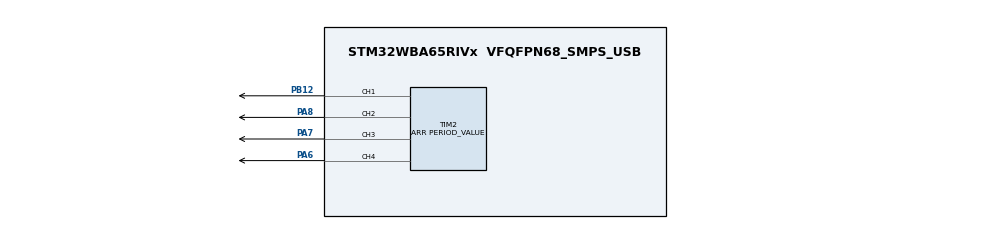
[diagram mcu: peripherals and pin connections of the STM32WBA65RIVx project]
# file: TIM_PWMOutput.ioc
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CORTEX_M33_NS.userName=CORTEX_M33
Mcu.Family=STM32WBA
Mcu.Name=STM32WBA65RIVx
Mcu.Package=VFQFPN68_SMPS_USB
NVIC.PriorityGroup=NVIC_PRIORITYGROUP_4
OSC_IN.Mode=HSE-External-Oscillator
OSC_IN.PinAttribute=CortexM33
OSC_IN.Signal=RCC_OSC_IN
OSC_OUT.Mode=HSE-External-Oscillator
OSC_OUT.PinAttribute=CortexM33
OSC_OUT.Signal=RCC_OSC_OUT
PA6.GPIO_PuPd=GPIO_PULLUP
PA6.GPIO_Speed=GPIO_SPEED_FREQ_HIGH
PA6.PinAttribute=CortexM33
PA6.Signal=S_TIM2_CH4
PA7.GPIO_PuPd=GPIO_PULLUP
PA7.GPIO_Speed=GPIO_SPEED_FREQ_HIGH
PA7.PinAttribute=CortexM33
PA7.Signal=S_TIM2_CH3
PA8.GPIO_PuPd=GPIO_PULLUP
PA8.GPIO_Speed=GPIO_SPEED_FREQ_HIGH
PA8.PinAttribute=CortexM33
PA8.Signal=S_TIM2_CH2
PB12.GPIO_PuPd=GPIO_PULLUP
PB12.GPIO_Speed=GPIO_SPEED_FREQ_HIGH
PB12.PinAttribute=CortexM33
PB12.Signal=S_TIM2_CH1
ProjectManager.HeapSize=0x200
ProjectManager.StackSize=0x400
ProjectManager.TargetToolchain=EWARM V9.20
RCC.ADCFreq_Value=100000000
RCC.AHB5CLKDivider=DIV4
RCC.AHBFreq_Value=100000000
RCC.APB1Freq_Value=100000000
RCC.APB1TimFreq_Value=100000000
RCC.APB2Freq_Value=100000000
RCC.APB2TimFreq_Value=100000000
RCC.CortexFreq_Value=12500000
RCC.HCLKFreq_Value=100000000
RCC.HSE_VALUE=32000000
RCC.HSI_VALUE=16000000
RCC.LSE_VALUE=32768
RCC.LSI1_VALUE=32000
RCC.LSI2_VALUE=32000
RCC.PLLFRACN=4096
RCC.PLLM=2
RCC.PLLN=12
RCC.PLLSourceVirtual=RCC_PLLSOURCE_HSE
RCC.SYSCLKFreq_VALUE=100000000
RCC.SYSCLKSourceVirtual=RCC_SYSCLKSOURCE_PLLCLK
RCC.VCOOutputFreq_Value=200000000
SH.S_TIM2_CH1.0=TIM2_CH1,PWM Generation1 CH1
SH.S_TIM2_CH2.0=TIM2_CH2,PWM Generation2 CH2
SH.S_TIM2_CH3.0=TIM2_CH3,PWM Generation3 CH3
SH.S_TIM2_CH4.0=TIM2_CH4,PWM Generation4 CH4
TIM2.AutoReloadPreload=TIM_AUTORELOAD_PRELOAD_DISABLE
TIM2.Channel-PWM\ Generation1\ CH1=TIM_CHANNEL_1
TIM2.Channel-PWM\ Generation2\ CH2=TIM_CHANNEL_2
TIM2.Channel-PWM\ Generation3\ CH3=TIM_CHANNEL_3
TIM2.Channel-PWM\ Generation4\ CH4=TIM_CHANNEL_4
TIM2.ClearInputSource=TIM_CLEARINPUTSOURCE_NONE
TIM2.ClockDivision=TIM_CLOCKDIVISION_DIV1
TIM2.CounterMode=TIM_COUNTERMODE_UP
TIM2.OC1Preload_PWM=ENABLE
TIM2.OC2Preload_PWM=ENABLE
TIM2.OC3Preload_PWM=ENABLE
TIM2.OC4Preload_PWM=ENABLE
TIM2.OCFastMode_PWM-PWM\ Generation1\ CH1=TIM_OCFAST_DISABLE
TIM2.OCFastMode_PWM-PWM\ Generation2\ CH2=TIM_OCFAST_DISABLE
TIM2.OCFastMode_PWM-PWM\ Generation3\ CH3=TIM_OCFAST_DISABLE
TIM2.OCFastMode_PWM-PWM\ Generation4\ CH4=TIM_OCFAST_DISABLE
TIM2.OCMode_PWM-PWM\ Generation1\ CH1=TIM_OCMODE_PWM1
TIM2.OCMode_PWM-PWM\ Generation2\ CH2=TIM_OCMODE_PWM1
TIM2.OCMode_PWM-PWM\ Generation3\ CH3=TIM_OCMODE_PWM1
TIM2.OCMode_PWM-PWM\ Generation4\ CH4=TIM_OCMODE_PWM1
TIM2.OCPolarity_1=TIM_OCPOLARITY_HIGH
TIM2.OCPolarity_2=TIM_OCPOLARITY_HIGH
TIM2.OCPolarity_3=TIM_OCPOLARITY_HIGH
TIM2.OCPolarity_4=TIM_OCPOLARITY_HIGH
TIM2.Period=PERIOD_VALUE
TIM2.Prescaler=PRESCALER_VALUE
TIM2.PulseNoDither_1=PULSE1_VALUE
TIM2.PulseNoDither_2=PULSE2_VALUE
TIM2.PulseNoDither_3=PULSE3_VALUE
TIM2.PulseNoDither_4=PULSE4_VALUE
TIM2.TIM_MasterOutputTrigger=TIM_TRGO_RESET
TIM2.TIM_MasterSlaveMode=TIM_MASTERSLAVEMODE_DISABLE
VP_CORTEX_M33_NS_VS_Hclk.Mode=Hclk_Mode
VP_ICACHE_VS_ICACHE.Mode=DirectMappedCache
VP_PWR_VS_SECSignals.Mode=Security/Privilege
board=custom

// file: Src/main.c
/* USER CODE BEGIN Header */
/**
  ******************************************************************************
  * @file    TIM/TIM_PWMOutput/Src/main.c
  * @author  MCD Application Team
  * @brief   This sample code shows how to use STM32WBAxx TIM HAL API to generate
  *          4 signals in PWM.
  ******************************************************************************
  * @attention
  *
  * Copyright (c) 2024 STMicroelectronics.
  * All rights reserved.
  *
  * This software is licensed under terms that can be found in the LICENSE file
  * in the root directory of this software component.
  * If no LICENSE file comes with this software, it is provided AS-IS.
  *
  ******************************************************************************
  */
/* USER CODE END Header */
#include "main.h"

TIM_HandleTypeDef htim2;

void SystemClock_Config(void);
static void MX_GPIO_Init(void);
static void MX_TIM2_Init(void);
static void MX_ICACHE_Init(void);

int main(void)
{

  /* USER CODE BEGIN 1 */

  /* STM32WBAxx HAL library initialization:
       - Systick timer is configured by default as source of time base, but user
             can eventually implement his proper time base source (a general purpose
             timer for example or other time source), keeping in mind that Time base
             duration should be kept 1ms since PPP_TIMEOUT_VALUEs are defined and
             handled in milliseconds basis.
       - Set NVIC Group Priority to 4
       - Low Level Initialization
     */
  /* USER CODE END 1 */

  /* MCU Configuration--------------------------------------------------------*/

  /* Reset of all peripherals, Initializes the Flash interface and the Systick. */
  HAL_Init();

  /* Configure the system clock */
  SystemClock_Config();

  /* USER CODE BEGIN SysInit */

  /* Configure LD3 */
  BSP_LED_Init(LD3);

  /* USER CODE END SysInit */

  /* Initialize all configured peripherals */
  MX_GPIO_Init();
  MX_TIM2_Init();
  MX_ICACHE_Init();
  /* USER CODE BEGIN 2 */

/*## Start PWM signals generation #######################################*/
  /* Start channel 1 */
  if (HAL_TIM_PWM_Start(&htim2, TIM_CHANNEL_1) != HAL_OK)
  {
    /* PWM Generation Error */
    Error_Handler();
  }
  /* Start channel 2 */
  if (HAL_TIM_PWM_Start(&htim2, TIM_CHANNEL_2) != HAL_OK)
  {
    /* PWM Generation Error */
    Error_Handler();
  }
  /* Start channel 3 */
  if (HAL_TIM_PWM_Start(&htim2, TIM_CHANNEL_3) != HAL_OK)
  {
    /* PWM generation Error */
    Error_Handler();
  }
  /* Start channel 4 */
  if (HAL_TIM_PWM_Start(&htim2, TIM_CHANNEL_4) != HAL_OK)
  {
    /* PWM generation Error */
    Error_Handler();
  }

  /* USER CODE END 2 */

  /* Infinite loop */
  while (1)
  {

  }
}

void SystemClock_Config(void)
{
  RCC_OscInitTypeDef RCC_OscInitStruct = {0};
  RCC_ClkInitTypeDef RCC_ClkInitStruct = {0};

  /** Supply configuration update enable
  */
  HAL_PWREx_ConfigSupply(PWR_LDO_SUPPLY);

  /** Configure the main internal regulator output voltage
  */
  if (HAL_PWREx_ControlVoltageScaling(PWR_REGULATOR_VOLTAGE_SCALE1) != HAL_OK)
  {
    Error_Handler();
  }

  /** Initializes the CPU, AHB and APB busses clocks
  */
  RCC_OscInitStruct.OscillatorType = RCC_OSCILLATORTYPE_HSE;
  RCC_OscInitStruct.HSEState = RCC_HSE_ON;
  RCC_OscInitStruct.HSEDiv = RCC_HSE_DIV1;
  RCC_OscInitStruct.PLL1.PLLState = RCC_PLL_ON;
  RCC_OscInitStruct.PLL1.PLLSource = RCC_PLLSOURCE_HSE;
  RCC_OscInitStruct.PLL1.PLLM = 2;
  RCC_OscInitStruct.PLL1.PLLN = 12;
  RCC_OscInitStruct.PLL1.PLLP = 2;
  RCC_OscInitStruct.PLL1.PLLQ = 2;
  RCC_OscInitStruct.PLL1.PLLR = 2;
  RCC_OscInitStruct.PLL1.PLLFractional = 4096;
  if (HAL_RCC_OscConfig(&RCC_OscInitStruct) != HAL_OK)
  {
    Error_Handler();
  }

  /** Initializes the CPU, AHB and APB busses clocks
  */
  RCC_ClkInitStruct.ClockType = RCC_CLOCKTYPE_HCLK|RCC_CLOCKTYPE_SYSCLK
                              |RCC_CLOCKTYPE_PCLK1|RCC_CLOCKTYPE_PCLK2
                              |RCC_CLOCKTYPE_PCLK7|RCC_CLOCKTYPE_HCLK5;
  RCC_ClkInitStruct.SYSCLKSource = RCC_SYSCLKSOURCE_PLLCLK;
  RCC_ClkInitStruct.AHBCLKDivider = RCC_SYSCLK_DIV1;
  RCC_ClkInitStruct.APB1CLKDivider = RCC_HCLK_DIV1;
  RCC_ClkInitStruct.APB2CLKDivider = RCC_HCLK_DIV1;
  RCC_ClkInitStruct.APB7CLKDivider = RCC_HCLK_DIV1;
  RCC_ClkInitStruct.AHB5_PLL1_CLKDivider = RCC_SYSCLK_PLL1_DIV4;
  RCC_ClkInitStruct.AHB5_HSEHSI_CLKDivider = RCC_SYSCLK_HSEHSI_DIV1;

  if (HAL_RCC_ClockConfig(&RCC_ClkInitStruct, FLASH_LATENCY_3) != HAL_OK)
  {
    Error_Handler();
  }
}

static void MX_ICACHE_Init(void)
{

  /** Enable instruction cache in 1-way (direct mapped cache)
  */
  if (HAL_ICACHE_ConfigAssociativityMode(ICACHE_1WAY) != HAL_OK)
  {
    Error_Handler();
  }
  if (HAL_ICACHE_Enable() != HAL_OK)
  {
    Error_Handler();
  }

}

static void MX_TIM2_Init(void)
{

  TIM_MasterConfigTypeDef sMasterConfig = {0};
  TIM_OC_InitTypeDef sConfigOC = {0};

  htim2.Instance = TIM2;
  htim2.Init.Prescaler = PRESCALER_VALUE;
  htim2.Init.CounterMode = TIM_COUNTERMODE_UP;
  htim2.Init.Period = PERIOD_VALUE;
  htim2.Init.ClockDivision = TIM_CLOCKDIVISION_DIV1;
  htim2.Init.AutoReloadPreload = TIM_AUTORELOAD_PRELOAD_DISABLE;
  if (HAL_TIM_PWM_Init(&htim2) != HAL_OK)
  {
    Error_Handler();
  }
  sMasterConfig.MasterOutputTrigger = TIM_TRGO_RESET;
  sMasterConfig.MasterSlaveMode = TIM_MASTERSLAVEMODE_DISABLE;
  if (HAL_TIMEx_MasterConfigSynchronization(&htim2, &sMasterConfig) != HAL_OK)
  {
    Error_Handler();
  }
  sConfigOC.OCMode = TIM_OCMODE_PWM1;
  sConfigOC.Pulse = PULSE1_VALUE;
  sConfigOC.OCPolarity = TIM_OCPOLARITY_HIGH;
  sConfigOC.OCFastMode = TIM_OCFAST_DISABLE;
  if (HAL_TIM_PWM_ConfigChannel(&htim2, &sConfigOC, TIM_CHANNEL_1) != HAL_OK)
  {
    Error_Handler();
  }
  sConfigOC.Pulse = PULSE2_VALUE;
  if (HAL_TIM_PWM_ConfigChannel(&htim2, &sConfigOC, TIM_CHANNEL_2) != HAL_OK)
  {
    Error_Handler();
  }
  sConfigOC.Pulse = PULSE3_VALUE;
  if (HAL_TIM_PWM_ConfigChannel(&htim2, &sConfigOC, TIM_CHANNEL_3) != HAL_OK)
  {
    Error_Handler();
  }
  sConfigOC.Pulse = PULSE4_VALUE;
  if (HAL_TIM_PWM_ConfigChannel(&htim2, &sConfigOC, TIM_CHANNEL_4) != HAL_OK)
  {
    Error_Handler();
  }
  HAL_TIM_MspPostInit(&htim2);

}

static void MX_GPIO_Init(void)
{

  /* GPIO Ports Clock Enable */
  __HAL_RCC_GPIOB_CLK_ENABLE();
  __HAL_RCC_GPIOA_CLK_ENABLE();

}

void Error_Handler(void)
{
  /* USER CODE BEGIN Error_Handler_Debug */
  /* Turn LD3 on */
  BSP_LED_On(LD3);
  while(1)
  {
  }
  /* USER CODE END Error_Handler_Debug */
}
